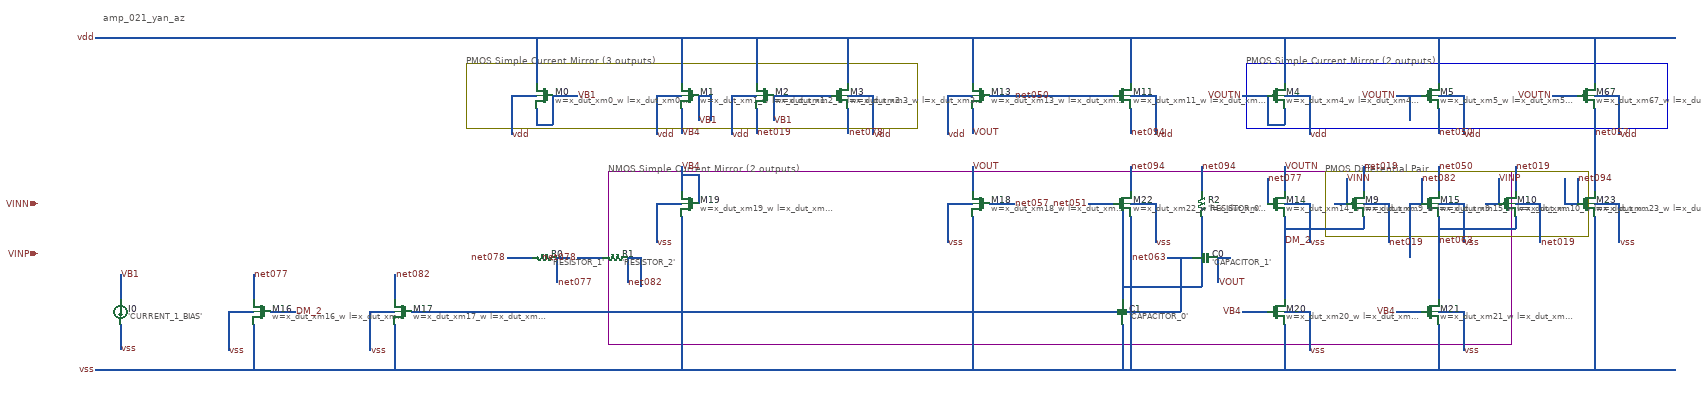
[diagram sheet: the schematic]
v {xschem version=3.4.6 file_version=1.2}
G {}
K {}
V {}
S {}
E {}
T {amp_021_yan_az} -1910 -200 0 0 0.4 0.4 {}
C {devices/capa_np.sym} 740 390 1 0 {name=C0 value='CAPACITOR_1'}
C {devices/capa_np.sym} 540 520 0 0 {name=C1 value='CAPACITOR_0'}
C {devices/isource_np.sym} -1870 520 0 0 {name=I0 value='CURRENT_1_BIAS'}
C {devices/res_np.sym} -850 390 1 0 {name=R0 value='RESISTOR_1'}
C {devices/res_np.sym} -680 390 1 0 {name=R1 value='RESISTOR_2'}
C {devices/res_np.sym} 730 260 0 0 {name=R2 value='RESISTOR_0'}
C {devices/sg13_lv_pmos_np.sym} -850 0 0 1 {name=M0 model=sg13_lv_pmos spiceprefix=X w=x_dut_xm0_w l=x_dut_xm0_l m=x_dut_xm0_m}
C {devices/sg13_lv_pmos_np.sym} -500 0 0 1 {name=M1 model=sg13_lv_pmos spiceprefix=X w=x_dut_xm1_w l=x_dut_xm1_l m=x_dut_xm1_m}
C {devices/sg13_lv_pmos_np.sym} 1465 260 0 0 {name=M10 model=sg13_lv_pmos spiceprefix=X w=x_dut_xm10_w l=x_dut_xm10_l m=x_dut_xm10_m}
C {devices/sg13_lv_pmos_np.sym} 540 0 0 0 {name=M11 model=sg13_lv_pmos spiceprefix=X w=x_dut_xm11_w l=x_dut_xm11_l m=x_dut_xm11_m}
C {devices/sg13_lv_pmos_np.sym} 200 0 0 1 {name=M13 model=sg13_lv_pmos spiceprefix=X w=x_dut_xm13_w l=x_dut_xm13_l m=x_dut_xm13_m}
C {devices/sg13_lv_nmos_np.sym} 910 260 0 0 {name=M14 model=sg13_lv_nmos spiceprefix=X w=x_dut_xm14_w l=x_dut_xm14_l m=x_dut_xm14_m}
C {devices/sg13_lv_nmos_np.sym} 1280 260 0 0 {name=M15 model=sg13_lv_nmos spiceprefix=X w=x_dut_xm15_w l=x_dut_xm15_l m=x_dut_xm15_m}
C {devices/sg13_lv_nmos_np.sym} -1530 520 0 1 {name=M16 model=sg13_lv_nmos spiceprefix=X w=x_dut_xm16_w l=x_dut_xm16_l m=x_dut_xm16_m}
C {devices/sg13_lv_nmos_np.sym} -1190 520 0 1 {name=M17 model=sg13_lv_nmos spiceprefix=X w=x_dut_xm17_w l=x_dut_xm17_l m=x_dut_xm17_m}
C {devices/sg13_lv_nmos_np.sym} 200 260 0 1 {name=M18 model=sg13_lv_nmos spiceprefix=X w=x_dut_xm18_w l=x_dut_xm18_l m=x_dut_xm18_m}
C {devices/sg13_lv_nmos_np.sym} -500 260 0 1 {name=M19 model=sg13_lv_nmos spiceprefix=X w=x_dut_xm19_w l=x_dut_xm19_l m=x_dut_xm19_m}
C {devices/sg13_lv_pmos_np.sym} -320 0 0 1 {name=M2 model=sg13_lv_pmos spiceprefix=X w=x_dut_xm2_w l=x_dut_xm2_l m=x_dut_xm2_m}
C {devices/sg13_lv_nmos_np.sym} 910 520 0 0 {name=M20 model=sg13_lv_nmos spiceprefix=X w=x_dut_xm20_w l=x_dut_xm20_l m=x_dut_xm20_m}
C {devices/sg13_lv_nmos_np.sym} 1280 520 0 0 {name=M21 model=sg13_lv_nmos spiceprefix=X w=x_dut_xm21_w l=x_dut_xm21_l m=x_dut_xm21_m}
C {devices/sg13_lv_nmos_np.sym} 540 260 0 0 {name=M22 model=sg13_lv_nmos spiceprefix=X w=x_dut_xm22_w l=x_dut_xm22_l m=x_dut_xm22_m}
C {devices/sg13_lv_nmos_np.sym} 1655 260 0 0 {name=M23 model=sg13_lv_nmos spiceprefix=X w=x_dut_xm23_w l=x_dut_xm23_l m=x_dut_xm23_m}
C {devices/sg13_lv_pmos_np.sym} -140 0 0 0 {name=M3 model=sg13_lv_pmos spiceprefix=X w=x_dut_xm3_w l=x_dut_xm3_l m=x_dut_xm3_m}
C {devices/sg13_lv_pmos_np.sym} 910 0 0 0 {name=M4 model=sg13_lv_pmos spiceprefix=X w=x_dut_xm4_w l=x_dut_xm4_l m=x_dut_xm4_m}
C {devices/sg13_lv_pmos_np.sym} 1280 0 0 0 {name=M5 model=sg13_lv_pmos spiceprefix=X w=x_dut_xm5_w l=x_dut_xm5_l m=x_dut_xm5_m}
C {devices/sg13_lv_pmos_np.sym} 1655 0 0 0 {name=M67 model=sg13_lv_pmos spiceprefix=X w=x_dut_xm67_w l=x_dut_xm67_l m=x_dut_xm67_m}
C {devices/sg13_lv_pmos_np.sym} 1100 260 0 0 {name=M9 model=sg13_lv_pmos spiceprefix=X w=x_dut_xm9_w l=x_dut_xm9_l m=x_dut_xm9_m}
N -1870 430 -1870 490 {}
N -1870 550 -1870 610 {}
N -1610 520 -1610 614 {}
N -1550 430 -1550 490 {}
N -1550 550 -1550 660 {}
N -1270 520 -1270 614 {}
N -1210 430 -1210 490 {}
N -1210 550 -1210 660 {}
N -930 0 -930 94 {}
N -870 -140 -870 -30 {}
N -870 30 -870 70 {}
N -830 0 -830 70 {}
N -820 390 -820 450 {}
N -650 390 -650 450 {}
N -620 390 -620 460 {}
N -580 0 -580 94 {}
N -580 260 -580 354 {}
N -520 -140 -520 -30 {}
N -520 30 -520 90 {}
N -520 170 -520 230 {}
N -520 290 -520 660 {}
N -480 0 -480 60 {}
N -480 190 -480 260 {}
N -450 0 -450 60 {}
N -400 0 -400 94 {}
N -340 -140 -340 -30 {}
N -340 30 -340 90 {}
N -300 0 -300 60 {}
N -120 -140 -120 -30 {}
N -120 30 -120 90 {}
N -60 0 -60 94 {}
N 120 0 120 94 {}
N 120 260 120 354 {}
N 180 -140 180 -30 {}
N 180 30 180 90 {}
N 180 170 180 230 {}
N 180 290 180 660 {}
N 540 260 540 490 {}
N 540 550 540 660 {}
N 560 -140 560 -30 {}
N 560 30 560 90 {}
N 560 170 560 230 {}
N 560 290 560 660 {}
N 620 0 620 94 {}
N 620 260 620 354 {}
N 680 390 680 520 {}
N 730 170 730 230 {}
N 730 290 730 460 {}
N 770 390 770 450 {}
N 890 0 890 70 {}
N 890 200 890 260 {}
N 930 -140 930 -30 {}
N 930 30 930 70 {}
N 930 170 930 230 {}
N 930 290 930 490 {}
N 930 550 930 660 {}
N 990 0 990 94 {}
N 990 260 990 354 {}
N 990 520 990 614 {}
N 1080 200 1080 260 {}
N 1120 170 1120 230 {}
N 1120 290 1120 320 {}
N 1180 260 1180 354 {}
N 1230 0 1230 60 {}
N 1230 260 1230 390 {}
N 1260 200 1260 260 {}
N 1300 -140 1300 -30 {}
N 1300 30 1300 90 {}
N 1300 170 1300 230 {}
N 1300 290 1300 490 {}
N 1300 550 1300 660 {}
N 1360 0 1360 94 {}
N 1360 260 1360 354 {}
N 1360 520 1360 614 {}
N 1445 200 1445 260 {}
N 1485 170 1485 230 {}
N 1485 290 1485 320 {}
N 1545 260 1545 354 {}
N 1605 200 1605 260 {}
N 1635 200 1635 260 {}
N 1675 -140 1675 -30 {}
N 1675 30 1675 230 {}
N 1675 290 1675 660 {}
N 1735 0 1735 94 {}
N 1735 260 1735 354 {}
N -1930 -140 1870 -140 {}
N -930 0 -870 0 {}
N -830 0 -770 0 {}
N -580 0 -520 0 {}
N -480 0 -450 0 {}
N -400 0 -340 0 {}
N -300 0 -160 0 {}
N -120 0 -60 0 {}
N 120 0 180 0 {}
N 220 0 520 0 {}
N 560 0 620 0 {}
N 830 0 890 0 {}
N 930 0 990 0 {}
N 1200 0 1260 0 {}
N 1300 0 1360 0 {}
N 1575 0 1635 0 {}
N 1675 0 1735 0 {}
N -870 70 -830 70 {}
N 890 70 930 70 {}
N -520 190 -480 190 {}
N -580 260 -520 260 {}
N 120 260 180 260 {}
N 220 260 280 260 {}
N 460 260 540 260 {}
N 560 260 620 260 {}
N 930 260 990 260 {}
N 1050 260 1080 260 {}
N 1120 260 1180 260 {}
N 1230 260 1260 260 {}
N 1300 260 1360 260 {}
N 1415 260 1445 260 {}
N 1485 260 1545 260 {}
N 1605 260 1635 260 {}
N 1675 260 1735 260 {}
N 930 320 1120 320 {}
N 1300 320 1485 320 {}
N -940 390 -880 390 {}
N -820 390 -790 390 {}
N -770 390 -710 390 {}
N -650 390 -620 390 {}
N 650 390 710 390 {}
N 770 390 800 390 {}
N 540 460 730 460 {}
N -1610 520 -1550 520 {}
N -1510 520 -1450 520 {}
N -1270 520 -1210 520 {}
N -1170 520 680 520 {}
N 830 520 890 520 {}
N 930 520 990 520 {}
N 1200 520 1260 520 {}
N 1300 520 1360 520 {}
N -1930 660 1870 660 {}
C {devices/lab_wire.sym} -1930 -140 0 0 {name=l0 lab=vdd}
C {devices/lab_wire.sym} -1930 660 0 0 {name=l1 lab=vss}
C {devices/lab_wire.sym} -1450 520 0 1 {name=l2 lab=DM_2}
C {devices/lab_wire.sym} 930 350 2 0 {name=l3 lab=DM_2}
C {devices/lab_wire.sym} -770 0 0 1 {name=l4 lab=VB1}
C {devices/lab_wire.sym} -480 60 2 0 {name=l5 lab=VB1}
C {devices/lab_wire.sym} -300 60 2 0 {name=l6 lab=VB1}
C {devices/lab_wire.sym} -520 90 2 0 {name=l7 lab=VB4}
C {devices/lab_wire.sym} -520 170 0 1 {name=l8 lab=VB4}
C {devices/lab_wire.sym} 830 520 0 0 {name=l9 lab=VB4}
C {devices/lab_wire.sym} 1200 520 0 0 {name=l10 lab=VB4}
C {devices/lab_wire.sym} 1080 200 0 1 {name=l11 lab=VINN}
C {devices/lab_wire.sym} 1445 200 0 1 {name=l12 lab=VINP}
C {devices/lab_wire.sym} 180 90 2 0 {name=l13 lab=VOUT}
C {devices/lab_wire.sym} 180 170 0 1 {name=l14 lab=VOUT}
C {devices/lab_wire.sym} 770 450 2 0 {name=l15 lab=VOUT}
C {devices/lab_wire.sym} 830 0 0 0 {name=l16 lab=VOUTN}
C {devices/lab_wire.sym} 930 170 0 1 {name=l17 lab=VOUTN}
C {devices/lab_wire.sym} 1200 0 0 0 {name=l18 lab=VOUTN}
C {devices/lab_wire.sym} 1575 0 0 0 {name=l19 lab=VOUTN}
C {devices/lab_wire.sym} -340 90 2 0 {name=l20 lab=net019}
C {devices/lab_wire.sym} 1120 170 0 1 {name=l21 lab=net019}
C {devices/lab_wire.sym} 1485 170 0 1 {name=l22 lab=net019}
C {devices/lab_wire.sym} 280 0 0 1 {name=l23 lab=net050}
C {devices/lab_wire.sym} 1300 90 2 0 {name=l24 lab=net050}
C {devices/lab_wire.sym} 1300 170 0 1 {name=l25 lab=net050}
C {devices/lab_wire.sym} 460 260 0 0 {name=l26 lab=net051}
C {devices/lab_wire.sym} 280 260 0 1 {name=l27 lab=net057}
C {devices/lab_wire.sym} 1675 90 2 0 {name=l28 lab=net057}
C {devices/lab_wire.sym} 650 390 0 0 {name=l29 lab=net063}
C {devices/lab_wire.sym} 1300 350 2 0 {name=l30 lab=net063}
C {devices/lab_wire.sym} -1550 430 0 1 {name=l31 lab=net077}
C {devices/lab_wire.sym} -820 450 2 0 {name=l32 lab=net077}
C {devices/lab_wire.sym} 890 200 0 1 {name=l33 lab=net077}
C {devices/lab_wire.sym} -940 390 0 0 {name=l34 lab=net078}
C {devices/lab_wire.sym} -770 390 0 0 {name=l35 lab=net078}
C {devices/lab_wire.sym} -120 90 2 0 {name=l36 lab=net078}
C {devices/lab_wire.sym} -1210 430 0 1 {name=l37 lab=net082}
C {devices/lab_wire.sym} -650 450 2 0 {name=l38 lab=net082}
C {devices/lab_wire.sym} 1260 200 0 1 {name=l39 lab=net082}
C {devices/lab_wire.sym} 560 90 2 0 {name=l40 lab=net094}
C {devices/lab_wire.sym} 560 170 0 1 {name=l41 lab=net094}
C {devices/lab_wire.sym} 730 170 0 1 {name=l42 lab=net094}
C {devices/lab_wire.sym} 1635 200 0 1 {name=l43 lab=net094}
C {devices/lab_wire.sym} 1545 354 2 0 {name=l44 lab=net019}
C {devices/lab_wire.sym} 1180 354 2 0 {name=l45 lab=net019}
C {devices/lab_wire.sym} -930 94 2 0 {name=l46 lab=vdd}
C {devices/lab_wire.sym} -580 94 2 0 {name=l47 lab=vdd}
C {devices/lab_wire.sym} 620 94 2 0 {name=l48 lab=vdd}
C {devices/lab_wire.sym} 120 94 2 0 {name=l49 lab=vdd}
C {devices/lab_wire.sym} -400 94 2 0 {name=l50 lab=vdd}
C {devices/lab_wire.sym} -60 94 2 0 {name=l51 lab=vdd}
C {devices/lab_wire.sym} 990 94 2 0 {name=l52 lab=vdd}
C {devices/lab_wire.sym} 1360 94 2 0 {name=l53 lab=vdd}
C {devices/lab_wire.sym} 1735 94 2 0 {name=l54 lab=vdd}
C {devices/lab_wire.sym} 990 354 2 0 {name=l55 lab=vss}
C {devices/lab_wire.sym} 1360 354 2 0 {name=l56 lab=vss}
C {devices/lab_wire.sym} -1610 614 2 0 {name=l57 lab=vss}
C {devices/lab_wire.sym} -1270 614 2 0 {name=l58 lab=vss}
C {devices/lab_wire.sym} 120 354 2 0 {name=l59 lab=vss}
C {devices/lab_wire.sym} -580 354 2 0 {name=l60 lab=vss}
C {devices/lab_wire.sym} 990 614 2 0 {name=l61 lab=vss}
C {devices/lab_wire.sym} 1360 614 2 0 {name=l62 lab=vss}
C {devices/lab_wire.sym} 620 354 2 0 {name=l63 lab=vss}
C {devices/lab_wire.sym} 1735 354 2 0 {name=l64 lab=vss}
C {devices/lab_wire.sym} -1870 610 2 0 {name=l65 lab=vss}
C {devices/lab_wire.sym} -1870 430 0 1 {name=l66 lab=VB1}
C {devices/ipin.sym} -2070 260 0 0 {name=p0 lab=VINN}
C {devices/ipin.sym} -2070 380 0 0 {name=p1 lab=VINP}
B 8 -1038 -78 48 78 {fill=0}
T {PMOS Simple Current Mirror (3 outputs)} -1038 -96 0 0 0.3 0.3 {layer=8}
B 10 -696 182 1476 598 {fill=0}
T {NMOS Simple Current Mirror (2 outputs)} -696 164 0 0 0.3 0.3 {layer=10}
B 12 840 -78 1851 78 {fill=0}
T {PMOS Simple Current Mirror (2 outputs)} 840 -96 0 0 0.3 0.3 {layer=12}
B 21 1030 182 1661 338 {fill=0}
T {PMOS Differential Pair} 1030 164 0 0 0.3 0.3 {layer=21}
